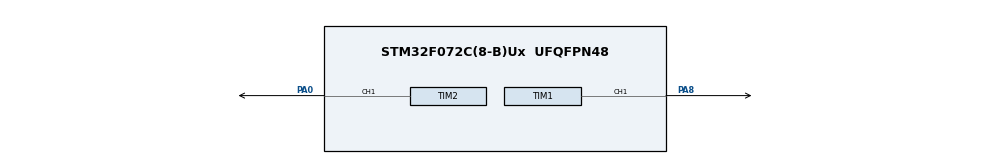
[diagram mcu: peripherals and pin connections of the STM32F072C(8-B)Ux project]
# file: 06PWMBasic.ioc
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Mcu.Family=STM32F0
Mcu.Name=STM32F072C(8-B)Ux
Mcu.Package=UFQFPN48
PA0.Signal=S_TIM2_CH1_ETR
PA13.Mode=Serial_Wire
PA13.Signal=SYS_SWDIO
PA14.Mode=Serial_Wire
PA14.Signal=SYS_SWCLK
PA8.Signal=S_TIM1_CH1
ProjectManager.HeapSize=0x200
ProjectManager.StackSize=0x400
ProjectManager.TargetToolchain=CMake
RCC.AHBFreq_Value=48000000
RCC.APB1Freq_Value=48000000
RCC.APB1TimFreq_Value=48000000
RCC.HCLKFreq_Value=48000000
RCC.PLLDivider=RCC_PREDIV_DIV2
RCC.PLLSourceVirtual=RCC_PLLSOURCE_HSI48
RCC.SYSCLKFreq_VALUE=48000000
RCC.SYSCLKSource=RCC_SYSCLKSOURCE_HSI48
SH.S_TIM1_CH1.0=TIM1_CH1,PWM Generation1 CH1
SH.S_TIM2_CH1_ETR.0=TIM2_CH1,PWM Generation1 CH1
TIM1.Channel-PWM\ Generation1\ CH1=TIM_CHANNEL_1
TIM1.Period=999
TIM1.Prescaler=47
TIM2.Channel-PWM\ Generation1\ CH1=TIM_CHANNEL_1
TIM2.Period=999
TIM2.Prescaler=47
board=custom

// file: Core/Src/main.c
/* USER CODE BEGIN Header */
/**
  ******************************************************************************
  * @file           : main.c
  * @brief          : Main program body
  ******************************************************************************
  * @attention
  *
  * Copyright (c) 2026 STMicroelectronics.
  * All rights reserved.
  *
  * This software is licensed under terms that can be found in the LICENSE file
  * in the root directory of this software component.
  * If no LICENSE file comes with this software, it is provided AS-IS.
  *
  ******************************************************************************
  */
/* USER CODE END Header */
#include "main.h"
#include "tim.h"
#include "gpio.h"

/* USER CODE BEGIN Includes */
/*
 * 双路 PWM 示例：STM32F072CBU6，系统及定时器时钟 48 MHz。
 * TIM1_CH1=PA8，TIM2_CH1=PA0；两路 PSC=47、ARR=999、CCR=500。
 * 计数频率=48 MHz/(47+1)=1 MHz，PWM=1 MHz/(999+1)=1 kHz，
 * 占空比=500/(999+1)=50%。可用示波器或逻辑分析仪观察。
 */
/* USER CODE END Includes */

void SystemClock_Config(void);

int main(void)
{

  /* MCU Configuration--------------------------------------------------------*/

  /* Reset of all peripherals, Initializes the Flash interface and the Systick. */
  HAL_Init();

  /* Configure the system clock */
  SystemClock_Config();

  /* Initialize all configured peripherals */
  MX_GPIO_Init();
  MX_TIM1_Init();
  MX_TIM2_Init();
  /* USER CODE BEGIN 2 */
  /* CCR 决定高电平持续的计数值；500/1000 对应 50% 占空比。 */
  /* 50% duty cycle: CCR1 / (ARR + 1) = 500 / 1000. */

  __HAL_TIM_SET_COMPARE(&htim1, TIM_CHANNEL_1, 500);

  if (HAL_TIM_PWM_Start(&htim1, TIM_CHANNEL_1) != HAL_OK)
  {
    Error_Handler();
  }

  __HAL_TIM_SET_COMPARE(&htim2, TIM_CHANNEL_1, 500);
  if (HAL_TIM_PWM_Start(&htim2, TIM_CHANNEL_1) != HAL_OK)
  {
    Error_Handler();
  }

  /* USER CODE END 2 */

  /* Infinite loop */
  while (1)
  {

  }
}

void SystemClock_Config(void)
{
  RCC_OscInitTypeDef RCC_OscInitStruct = {0};
  RCC_ClkInitTypeDef RCC_ClkInitStruct = {0};

  /** Initializes the RCC Oscillators according to the specified parameters
  * in the RCC_OscInitTypeDef structure.
  */
  RCC_OscInitStruct.OscillatorType = RCC_OSCILLATORTYPE_HSI48;
  RCC_OscInitStruct.HSI48State = RCC_HSI48_ON;
  RCC_OscInitStruct.PLL.PLLState = RCC_PLL_ON;
  RCC_OscInitStruct.PLL.PLLSource = RCC_PLLSOURCE_HSI48;
  RCC_OscInitStruct.PLL.PLLMUL = RCC_PLL_MUL2;
  RCC_OscInitStruct.PLL.PREDIV = RCC_PREDIV_DIV2;
  if (HAL_RCC_OscConfig(&RCC_OscInitStruct) != HAL_OK)
  {
    Error_Handler();
  }

  /** Initializes the CPU, AHB and APB buses clocks
  */
  RCC_ClkInitStruct.ClockType = RCC_CLOCKTYPE_HCLK|RCC_CLOCKTYPE_SYSCLK
                              |RCC_CLOCKTYPE_PCLK1;
  RCC_ClkInitStruct.SYSCLKSource = RCC_SYSCLKSOURCE_PLLCLK;
  RCC_ClkInitStruct.AHBCLKDivider = RCC_SYSCLK_DIV1;
  RCC_ClkInitStruct.APB1CLKDivider = RCC_HCLK_DIV1;

  if (HAL_RCC_ClockConfig(&RCC_ClkInitStruct, FLASH_LATENCY_1) != HAL_OK)
  {
    Error_Handler();
  }
}

void Error_Handler(void)
{
  __disable_irq();
  while (1)
  {
  }
}
